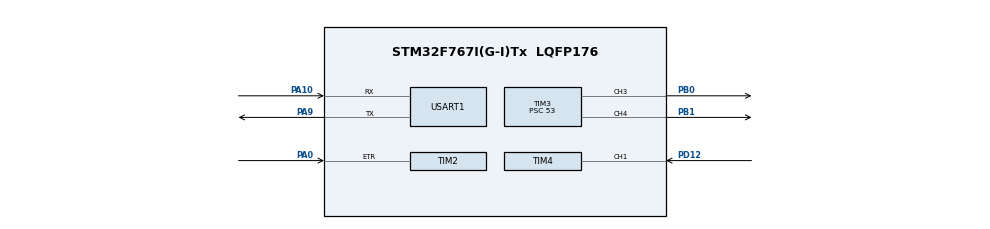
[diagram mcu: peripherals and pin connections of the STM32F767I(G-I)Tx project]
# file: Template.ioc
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Mcu.Family=STM32F7
Mcu.Name=STM32F767I(G-I)Tx
Mcu.Package=LQFP176
NVIC.PriorityGroup=NVIC_PRIORITYGROUP_4
NVIC.TIM4_IRQn=true\:1\:0\:true\:false\:true
NVIC.TIM5_IRQn=true\:0\:0\:false\:false\:true
PA0/WKUP.Signal=S_TIM2_CH1_ETR
PA10.Mode=Asynchronous
PA10.Signal=USART1_RX
PA9.Mode=Asynchronous
PA9.Signal=USART1_TX
PB0.Signal=S_TIM3_CH3
PB1.Signal=S_TIM3_CH4
PD12.Signal=S_TIM4_CH1
PH0/OSC_IN.Mode=HSE-External-Oscillator
PH0/OSC_IN.Signal=RCC_OSC_IN
PH1/OSC_OUT.Mode=HSE-External-Oscillator
PH1/OSC_OUT.Signal=RCC_OSC_OUT
ProjectManager.HeapSize=0x200
ProjectManager.StackSize=0x400
ProjectManager.TargetToolchain=MDK-ARM V5
RCC.AHBFreq_Value=216000000
RCC.APB1CLKDivider=RCC_HCLK_DIV4
RCC.APB1Freq_Value=54000000
RCC.APB1TimFreq_Value=108000000
RCC.APB2CLKDivider=RCC_HCLK_DIV2
RCC.APB2Freq_Value=108000000
RCC.APB2TimFreq_Value=216000000
RCC.CortexFreq_Value=216000000
RCC.HCLKFreq_Value=216000000
RCC.HSE_VALUE=25000000
RCC.HSI_VALUE=16000000
RCC.LSE_VALUE=32768
RCC.PLLM=25
RCC.PLLN=432
RCC.PLLSourceVirtual=RCC_PLLSOURCE_HSE
RCC.SYSCLKFreq_VALUE=216000000
RCC.SYSCLKSource=RCC_SYSCLKSOURCE_PLLCLK
RCC.USBFreq_Value=216000000
RCC.VCOOutputFreq_Value=432000000
SH.S_TIM2_CH1_ETR.0=TIM2_ETR,ClockSourceETR_Mode2
SH.S_TIM3_CH3.0=TIM3_CH3,PWM Generation3 CH3
SH.S_TIM3_CH4.0=TIM3_CH4,PWM Generation4 CH4
SH.S_TIM4_CH1.0=TIM4_CH1,Input_Capture1_from_TI1
TIM1.Period=65535
TIM1.Prescaler=35
TIM2.Period=0xFFFFFFFF
TIM3.Channel-PWM\ Generation3\ CH3=TIM_CHANNEL_3
TIM3.Channel-PWM\ Generation4\ CH4=TIM_CHANNEL_4
TIM3.OCPolarity_3=TIM_OCPOLARITY_LOW
TIM3.OCPolarity_4=TIM_OCPOLARITY_LOW
TIM3.Period=99
TIM3.Prescaler=53
TIM3.Pulse-PWM\ Generation3\ CH3=49
TIM3.Pulse-PWM\ Generation4\ CH4=49
TIM4.Period=0
TIM4.Prescaler=107
TIM5.Period=99
TIM5.Prescaler=1079
USART1.WordLength=UART_WORDLENGTH_8B
VP_TIM1_VS_ClockSourceINT.Mode=Internal
VP_TIM3_VS_ClockSourceINT.Mode=Internal
VP_TIM4_VS_ClockSourceINT.Mode=Internal
VP_TIM5_VS_ClockSourceINT.Mode=Internal
board=Template

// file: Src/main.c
/**
  ******************************************************************************
  * File Name          : main.c
  * Description        : Main program body
  ******************************************************************************
  *
  * COPYRIGHT(c) 2017 STMicroelectronics
  *
  * Redistribution and use in source and binary forms, with or without modification,
  * are permitted provided that the following conditions are met:
  *   1. Redistributions of source code must retain the above copyright notice,
  *      this list of conditions and the following disclaimer.
  *   2. Redistributions in binary form must reproduce the above copyright notice,
  *      this list of conditions and the following disclaimer in the documentation
  *      and/or other materials provided with the distribution.
  *   3. Neither the name of STMicroelectronics nor the names of its contributors
  *      may be used to endorse or promote products derived from this software
  *      without specific prior written permission.
  *
  * THIS SOFTWARE IS PROVIDED BY THE COPYRIGHT HOLDERS AND CONTRIBUTORS "AS IS"
  * AND ANY EXPRESS OR IMPLIED WARRANTIES, INCLUDING, BUT NOT LIMITED TO, THE
  * IMPLIED WARRANTIES OF MERCHANTABILITY AND FITNESS FOR A PARTICULAR PURPOSE ARE
  * DISCLAIMED. IN NO EVENT SHALL THE COPYRIGHT HOLDER OR CONTRIBUTORS BE LIABLE
  * FOR ANY DIRECT, INDIRECT, INCIDENTAL, SPECIAL, EXEMPLARY, OR CONSEQUENTIAL
  * DAMAGES (INCLUDING, BUT NOT LIMITED TO, PROCUREMENT OF SUBSTITUTE GOODS OR
  * SERVICES; LOSS OF USE, DATA, OR PROFITS; OR BUSINESS INTERRUPTION) HOWEVER
  * CAUSED AND ON ANY THEORY OF LIABILITY, WHETHER IN CONTRACT, STRICT LIABILITY,
  * OR TORT (INCLUDING NEGLIGENCE OR OTHERWISE) ARISING IN ANY WAY OUT OF THE USE
  * OF THIS SOFTWARE, EVEN IF ADVISED OF THE POSSIBILITY OF SUCH DAMAGE.
  *
  ******************************************************************************
  */
#include "stm32f7xx_hal.h"
#include "tim.h"
#include "usart.h"
#include "gpio.h"

/* USER CODE BEGIN PV */
/* Private variables ---------------------------------------------------------*/

/* USER CODE END PV */

void SystemClock_Config(void);
void Error_Handler(void);

/* USER CODE BEGIN PFP */
/* Private function prototypes -----------------------------------------------*/

/* USER CODE END PFP */

/* USER CODE BEGIN 0 */
uint8_t     TIM4CH1_CAPTURE_STA=0X80;		//输入捕获状态
uint32_t	TIM1_COUNTER_VAL[100];	        //定时器1计数组
uint32_t    TIM2_COUNTER_VAL[100];          //定时器2计数组
float	    TIM1_COUNTER_Val;	            //定时器1计数值
float       TIM2_COUNTER_Val;               //定时器2计数值
float       TIM_FREQ;                       //频率值
uint8_t     TIM4CH1_CAPTURE_GATE=0;         //预设闸门标志位
uint8_t     TIM4CH1_CAPTURE_STB=0;          //数组存满标志位
static uint8_t     i;                       //数组用
uint32_t	TIM1_COUNTER_TEMP;	            //定时器1计数滤波
uint32_t    TIM2_COUNTER_TEMP;              //定时器2计数滤波
/* USER CODE END 0 */

int main(void)
{

  /* MCU Configuration----------------------------------------------------------*/

  /* Reset of all peripherals, Initializes the Flash interface and the Systick. */
  HAL_Init();

  /* Configure the system clock */
  SystemClock_Config();

  /* Initialize all configured peripherals */
  MX_GPIO_Init();
  MX_TIM1_Init();
  MX_TIM2_Init();
  MX_TIM3_Init();
  MX_TIM4_Init();
  MX_USART1_UART_Init();
  MX_TIM5_Init();

  /* USER CODE BEGIN 2 */
  HAL_TIM_PWM_Start(&htim3, TIM_CHANNEL_4);  //使能PWM波
  HAL_TIM_PWM_Start(&htim3, TIM_CHANNEL_3);  //使能PWM波

  HAL_TIM_IC_Start_IT(&htim4,TIM_CHANNEL_1); //使能TIM4输入捕获中断
  __HAL_TIM_ENABLE_IT(&htim4, TIM_CHANNEL_1); //使能更新中断
  HAL_TIM_Base_Start_IT(&htim5);             //使能TIM5定时器中断

    __HAL_TIM_SET_COUNTER(&htim1,0);      //定时器1清零
    __HAL_TIM_SET_COUNTER(&htim2,0);      //定时器2清零

  TIM4CH1_CAPTURE_GATE = 1;                   //开启预设闸门
  /* USER CODE END 2 */

  /* Infinite loop */
  while (1)
  {
  /* USER CODE END WHILE */
    if(TIM4CH1_CAPTURE_STB)
    {
        TIM1_COUNTER_Val = (float) TIM1_COUNTER_TEMP / 100;
        TIM2_COUNTER_Val = (float) TIM2_COUNTER_TEMP / 100;
        TIM_FREQ = (TIM2_COUNTER_Val*2000.0)/TIM1_COUNTER_Val;

        printf("TIM1:%.2f\r\n",TIM1_COUNTER_Val);
        printf("TIM2:%.2f\r\n",TIM2_COUNTER_Val);
        printf("FREQ:%.2fKHZ\r\n",TIM_FREQ);

        TIM1_COUNTER_TEMP = 0;
        TIM2_COUNTER_TEMP = 0;
        TIM4CH1_CAPTURE_STB = 0;
        TIM4CH1_CAPTURE_STA |= 0X80;
        HAL_TIM_IC_Start_IT(&htim4,TIM_CHANNEL_1);
    }

  }

}

/** System Clock Configuration
*/
void SystemClock_Config(void)
{

  RCC_OscInitTypeDef RCC_OscInitStruct;
  RCC_ClkInitTypeDef RCC_ClkInitStruct;
  RCC_PeriphCLKInitTypeDef PeriphClkInitStruct;

  __HAL_RCC_PWR_CLK_ENABLE();

  __HAL_PWR_VOLTAGESCALING_CONFIG(PWR_REGULATOR_VOLTAGE_SCALE1);

  RCC_OscInitStruct.OscillatorType = RCC_OSCILLATORTYPE_HSE;
  RCC_OscInitStruct.HSEState = RCC_HSE_ON;
  RCC_OscInitStruct.PLL.PLLState = RCC_PLL_ON;
  RCC_OscInitStruct.PLL.PLLSource = RCC_PLLSOURCE_HSI;
  RCC_OscInitStruct.PLL.PLLM = 16;
  RCC_OscInitStruct.PLL.PLLN = 432;
  RCC_OscInitStruct.PLL.PLLP = 7;
  RCC_OscInitStruct.PLL.PLLQ = 9;
  if (HAL_RCC_OscConfig(&RCC_OscInitStruct) != HAL_OK)
  {
    Error_Handler();
  }

  if (HAL_PWREx_EnableOverDrive() != HAL_OK)
  {
    Error_Handler();
  }

  RCC_ClkInitStruct.ClockType = RCC_CLOCKTYPE_HCLK|RCC_CLOCKTYPE_SYSCLK
                              |RCC_CLOCKTYPE_PCLK1|RCC_CLOCKTYPE_PCLK2;
  RCC_ClkInitStruct.SYSCLKSource = RCC_SYSCLKSOURCE_PLLCLK;
  RCC_ClkInitStruct.AHBCLKDivider = RCC_SYSCLK_DIV1;
  RCC_ClkInitStruct.APB1CLKDivider = RCC_HCLK_DIV4;
  RCC_ClkInitStruct.APB2CLKDivider = RCC_HCLK_DIV2;
  if (HAL_RCC_ClockConfig(&RCC_ClkInitStruct, FLASH_LATENCY_7) != HAL_OK)
  {
    Error_Handler();
  }

  PeriphClkInitStruct.PeriphClockSelection = RCC_PERIPHCLK_USART1;
  PeriphClkInitStruct.Usart1ClockSelection = RCC_USART1CLKSOURCE_PCLK2;
  if (HAL_RCCEx_PeriphCLKConfig(&PeriphClkInitStruct) != HAL_OK)
  {
    Error_Handler();
  }

  HAL_SYSTICK_Config(HAL_RCC_GetHCLKFreq()/1000);

  HAL_SYSTICK_CLKSourceConfig(SYSTICK_CLKSOURCE_HCLK);

  /* SysTick_IRQn interrupt configuration */
  HAL_NVIC_SetPriority(SysTick_IRQn, 0, 0);
}

/* USER CODE BEGIN 4 */
//定时器TIM4输入捕获中断处理回调函数，该函数在HAL_TIM_IRQHandler中会被调用
void HAL_TIM_IC_CaptureCallback(TIM_HandleTypeDef *htim)//捕获中断发生时执行
{
                if(TIM4CH1_CAPTURE_GATE==0)
                {
                  if(TIM4CH1_CAPTURE_STA&0X40)	//第二次捕获到一个上升沿
                  {
                    TIM4CH1_CAPTURE_STA = 0X80;		//标记成功捕获到一次高电平脉宽
                    TIM1_COUNTER_VAL[i] = __HAL_TIM_GET_COUNTER(&htim1); //获得定时器1计数值
                    TIM2_COUNTER_VAL[i] = __HAL_TIM_GET_COUNTER(&htim2); //获得定时器2计数值

                    TIM1_COUNTER_TEMP += TIM1_COUNTER_VAL[i];
                    TIM2_COUNTER_TEMP += TIM2_COUNTER_VAL[i];

                    i++;
                        if(i == 100)
                        {
                            i = 0;
                            TIM4CH1_CAPTURE_STB = 1;
                            TIM4CH1_CAPTURE_STA = 0;
                            HAL_TIM_IC_Stop_IT(&htim4,TIM_CHANNEL_1);
                        }

                    HAL_TIM_Base_Stop(&htim1);            //关闭定时器1
                    HAL_TIM_Base_Stop(&htim2);            //关闭定时器2
                    __HAL_TIM_SET_COUNTER(&htim1,0);      //定时器1清零
                    __HAL_TIM_SET_COUNTER(&htim2,0);      //定时器2清零

                }

			}
                if(TIM4CH1_CAPTURE_GATE==1)
                {
                    if(TIM4CH1_CAPTURE_STA&0X80)//第一次捕获上升沿
			    {
                    TIM4CH1_CAPTURE_STA = 0X40;		//标记捕获到了上升沿
                    HAL_TIM_Base_Start(&htim1);     //使能定时器1，对标准信号计数
                    HAL_TIM_Base_Start(&htim2);     //使能定时器2，对被测信号计数
                }
			}

}
 //定时器TIM5溢出中断处理回调函数
void HAL_TIM_PeriodElapsedCallback(TIM_HandleTypeDef *htim)
{
    if(TIM5 == htim->Instance)
    {
       if(TIM4CH1_CAPTURE_GATE)
       {
            TIM4CH1_CAPTURE_GATE = 0;
       }
       else
       {
            TIM4CH1_CAPTURE_GATE = 1;
       }
    }
}

int fputc(int ch, FILE *f)
{
    HAL_UART_Transmit(&huart1, (uint8_t*)&ch ,1, 0xffff);

    return ch;
}
/* USER CODE END 4 */

void Error_Handler(void)
{
  while(1)
  {
  }
}

/************************ (C) COPYRIGHT STMicroelectronics *****END OF FILE****/
